VERSION 5.8 ;
BUSBITCHARS "[]" ;
DIVIDERCHAR "/" ;

SITE CoreSite
  CLASS CORE ;
  SIZE 1.0 BY 1.0 ;
END CoreSite

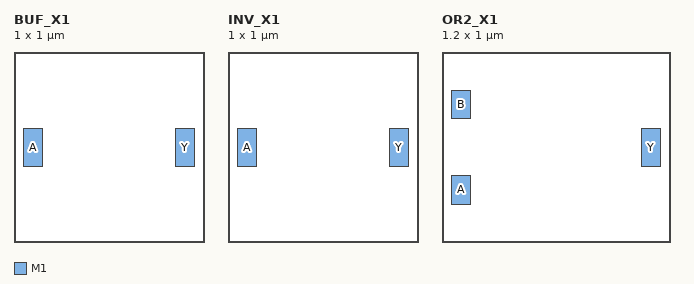
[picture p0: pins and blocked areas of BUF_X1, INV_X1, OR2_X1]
MACRO BUF_X1
  CLASS CORE ;
  ORIGIN 0 0 ;
  SIZE 1.0 BY 1.0 ;
  SYMMETRY X Y ;
  SITE CoreSite ;
  PIN A
    DIRECTION INPUT ;
    USE SIGNAL ;
    PORT
      LAYER M1 ;
      RECT 0.05 0.40 0.15 0.60 ;
    END
  END A
  PIN Y
    DIRECTION OUTPUT ;
    USE SIGNAL ;
    PORT
      LAYER M1 ;
      RECT 0.85 0.40 0.95 0.60 ;
    END
  END Y
END BUF_X1

MACRO INV_X1
  CLASS CORE ;
  ORIGIN 0 0 ;
  SIZE 1.0 BY 1.0 ;
  SYMMETRY X Y ;
  SITE CoreSite ;
  PIN A
    DIRECTION INPUT ;
    USE SIGNAL ;
    PORT
      LAYER M1 ;
      RECT 0.05 0.40 0.15 0.60 ;
    END
  END A
  PIN Y
    DIRECTION OUTPUT ;
    USE SIGNAL ;
    PORT
      LAYER M1 ;
      RECT 0.85 0.40 0.95 0.60 ;
    END
  END Y
END INV_X1

MACRO OR2_X1
  CLASS CORE ;
  ORIGIN 0 0 ;
  SIZE 1.2 BY 1.0 ;
  SYMMETRY X Y ;
  SITE CoreSite ;
  PIN A
    DIRECTION INPUT ;
    USE SIGNAL ;
    PORT
      LAYER M1 ;
      RECT 0.05 0.20 0.15 0.35 ;
    END
  END A
  PIN B
    DIRECTION INPUT ;
    USE SIGNAL ;
    PORT
      LAYER M1 ;
      RECT 0.05 0.65 0.15 0.80 ;
    END
  END B
  PIN Y
    DIRECTION OUTPUT ;
    USE SIGNAL ;
    PORT
      LAYER M1 ;
      RECT 1.05 0.40 1.15 0.60 ;
    END
  END Y
END OR2_X1

END LIBRARY
